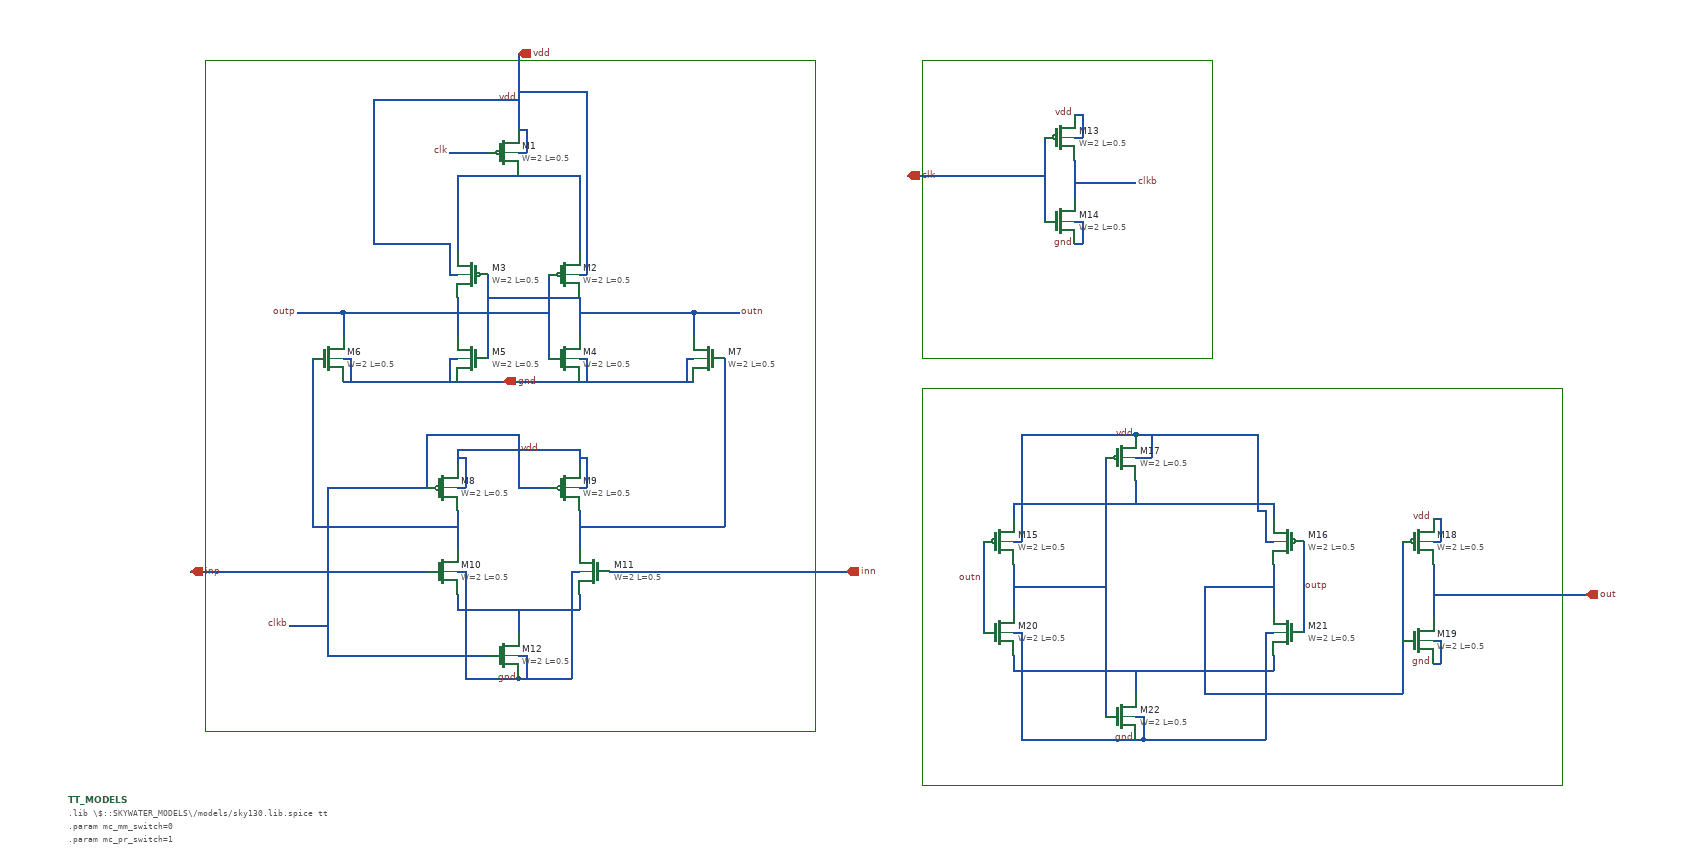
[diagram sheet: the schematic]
v {xschem version=3.4.1 file_version=1.2
}
G {}
K {}
V {}
S {}
E {}
L 4 1120 -1100 1120 -710 {}
L 4 1120 -710 1500 -710 {}
L 4 1500 -1100 1500 -710 {}
L 4 1120 -1100 1500 -1100 {}
L 4 180 -1100 180 -220 {}
L 4 180 -220 980 -220 {}
L 4 980 -1100 980 -220 {}
L 4 180 -1100 980 -1100 {}
L 4 1120 -670 1120 -150 {}
L 4 1120 -150 1960 -150 {}
L 4 1960 -670 1960 -150 {}
L 4 1120 -670 1960 -670 {}
N 510 -950 510 -850 {
lab=#net1}
N 510 -950 590 -950 {
lab=#net1}
N 590 -950 670 -950 {
lab=#net1}
N 670 -950 670 -850 {
lab=#net1}
N 510 -790 510 -740 {
lab=outp}
N 670 -790 670 -740 {
lab=outn}
N 550 -820 550 -710 {
lab=outn}
N 630 -820 630 -710 {
lab=outp}
N 510 -770 630 -770 {
lab=outp}
N 550 -790 670 -790 {
lab=outn}
N 360 -770 360 -740 {
lab=outp}
N 360 -770 510 -770 {
lab=outp}
N 670 -770 820 -770 {
lab=outn}
N 820 -770 820 -740 {
lab=outn}
N 360 -680 820 -680 {
lab=gnd}
N 510 -590 510 -570 {
lab=vdd}
N 510 -590 670 -590 {
lab=vdd}
N 670 -590 670 -570 {
lab=vdd}
N 470 -610 470 -540 {
lab=clkb}
N 470 -610 590 -610 {
lab=clkb}
N 590 -610 590 -540 {
lab=clkb}
N 590 -540 630 -540 {
lab=clkb}
N 510 -510 510 -460 {
lab=#net2}
N 670 -510 670 -460 {
lab=#net3}
N 320 -490 510 -490 {
lab=#net2}
N 320 -710 320 -490 {
lab=#net2}
N 670 -490 860 -490 {
lab=#net3}
N 860 -710 860 -490 {
lab=#net3}
N 510 -400 510 -380 {
lab=#net4}
N 510 -380 670 -380 {
lab=#net4}
N 670 -400 670 -380 {
lab=#net4}
N 590 -380 590 -350 {
lab=#net4}
N 340 -320 550 -320 {
lab=clkb}
N 340 -540 340 -320 {
lab=clkb}
N 340 -540 470 -540 {
lab=clkb}
N 820 -770 880 -770 {
lab=outn}
N 300 -770 360 -770 {
lab=outp}
N 710 -430 880 -430 {
lab=inn}
N 300 -430 470 -430 {
lab=inp}
N 1280 -1000 1280 -890 {
lab=clk}
N 1320 -970 1320 -920 {
lab=clkb}
N 1180 -950 1280 -950 {
lab=clk}
N 1320 -940 1400 -940 {
lab=clkb}
N 290 -360 340 -360 {
lab=clkb}
N 500 -980 550 -980 {
lab=clk}
N 1240 -520 1240 -500 {
lab=#net5}
N 1240 -520 1580 -520 {
lab=#net5}
N 1580 -520 1580 -500 {
lab=#net5}
N 1400 -550 1400 -520 {
lab=#net5}
N 1240 -440 1240 -380 {
lab=#net6}
N 1580 -440 1580 -380 {
lab=#net7}
N 1360 -580 1360 -240 {
lab=#net6}
N 1240 -320 1240 -300 {
lab=#net8}
N 1240 -300 1580 -300 {
lab=#net8}
N 1580 -320 1580 -300 {
lab=#net8}
N 1400 -300 1400 -270 {
lab=#net8}
N 1240 -410 1360 -410 {
lab=#net6}
N 1200 -470 1200 -350 {
lab=outn}
N 1620 -470 1620 -350 {
lab=outp}
N 1750 -470 1750 -340 {
lab=#net7}
N 1790 -440 1790 -370 {
lab=out}
N 1490 -410 1580 -410 {
lab=#net7}
N 1490 -410 1490 -270 {
lab=#net7}
N 1490 -270 1750 -270 {
lab=#net7}
N 1750 -340 1750 -270 {
lab=#net7}
N 1790 -400 1880 -400 {
lab=out}
N 1400 -580 1420 -580 {
lab=vdd}
N 1420 -610 1420 -580 {
lab=vdd}
N 1400 -610 1420 -610 {
lab=vdd}
N 1240 -470 1250 -470 {
lab=vdd}
N 1250 -510 1250 -470 {
lab=vdd}
N 1240 -350 1250 -350 {
lab=#net8}
N 1250 -350 1250 -310 {
lab=#net8}
N 1400 -240 1410 -240 {
lab=gnd}
N 1410 -240 1410 -210 {
lab=gnd}
N 1400 -210 1410 -210 {
lab=gnd}
N 1570 -350 1580 -350 {
lab=#net8}
N 1570 -350 1570 -310 {
lab=#net8}
N 1570 -470 1580 -470 {
lab=vdd}
N 1570 -510 1570 -470 {
lab=vdd}
N 1790 -470 1800 -470 {
lab=vdd}
N 1800 -500 1800 -470 {
lab=vdd}
N 1790 -500 1800 -500 {
lab=vdd}
N 1790 -340 1800 -340 {
lab=gnd}
N 1800 -340 1800 -310 {
lab=gnd}
N 1790 -310 1800 -310 {
lab=gnd}
N 590 -980 600 -980 {
lab=vdd}
N 600 -1010 600 -980 {
lab=vdd}
N 590 -1010 600 -1010 {
lab=vdd}
N 500 -820 510 -820 {
lab=vdd}
N 500 -860 500 -820 {
lab=vdd}
N 670 -820 680 -820 {
lab=vdd}
N 680 -860 680 -820 {
lab=vdd}
N 500 -710 510 -710 {
lab=gnd}
N 500 -710 500 -680 {
lab=gnd}
N 670 -710 680 -710 {
lab=gnd}
N 680 -710 680 -680 {
lab=gnd}
N 810 -710 820 -710 {
lab=gnd}
N 810 -710 810 -680 {
lab=gnd}
N 360 -710 370 -710 {
lab=gnd}
N 370 -710 370 -680 {
lab=gnd}
N 510 -540 520 -540 {
lab=vdd}
N 520 -580 520 -540 {
lab=vdd}
N 510 -580 520 -580 {
lab=vdd}
N 670 -540 680 -540 {
lab=vdd}
N 680 -580 680 -540 {
lab=vdd}
N 670 -580 680 -580 {
lab=vdd}
N 660 -430 670 -430 {
lab=#net4}
N 660 -430 660 -390 {
lab=#net4}
N 510 -430 520 -430 {
lab=#net4}
N 520 -430 520 -390 {
lab=#net4}
N 590 -320 600 -320 {
lab=gnd}
N 600 -320 600 -290 {
lab=gnd}
N 590 -290 600 -290 {
lab=gnd}
N 1320 -1000 1330 -1000 {
lab=vdd}
N 1330 -1030 1330 -1000 {
lab=vdd}
N 1320 -1030 1330 -1030 {
lab=vdd}
N 1320 -890 1330 -890 {
lab=gnd}
N 1330 -890 1330 -860 {
lab=gnd}
N 1320 -860 1330 -860 {
lab=gnd}
N 160 -430 300 -430 {
lab=inp}
N 880 -430 1020 -430 {
lab=inn}
N 1100 -950 1180 -950 {
lab=clk}
N 590 -1110 590 -1010 {
lab=vdd}
N 1880 -400 1990 -400 {
lab=out}
N 680 -1060 680 -860 {
lab=vdd}
N 590 -1060 680 -1060 {
lab=vdd}
N 400 -860 500 -860 {
lab=vdd}
N 400 -1050 400 -860 {
lab=vdd}
N 400 -1050 590 -1050 {
lab=vdd}
N 1250 -610 1250 -510 {
lab=vdd}
N 1250 -610 1400 -610 {
lab=vdd}
N 1400 -610 1560 -610 {
lab=vdd}
N 1560 -610 1560 -510 {
lab=vdd}
N 1560 -510 1570 -510 {
lab=vdd}
N 1250 -310 1250 -210 {}
N 1250 -210 1400 -210 {}
N 1570 -310 1570 -210 {}
N 1410 -210 1570 -210 {}
N 660 -390 660 -290 {}
N 590 -290 660 -290 {}
N 520 -390 520 -290 {}
N 520 -290 590 -290 {}
C {devices/code.sym} 0 -130 0 0 {name=TT_MODELS
only_toplevel=true
format="tcleval( @value )"
value=".lib \\\\$::SKYWATER_MODELS\\\\/models/sky130.lib.spice tt
.param mc_mm_switch=0
.param mc_pr_switch=1
"}
C {xschem_sky130/sky130_fd_pr/pfet_01v8.sym} 570 -980 0 0 {name=M1
L=0.5
W=2
nf=1
mult=1
ad="'int((nf+1)/2) * W/nf * 0.29'" 
pd="'2*int((nf+1)/2) * (W/nf + 0.29)'"
as="'int((nf+2)/2) * W/nf * 0.29'" 
ps="'2*int((nf+2)/2) * (W/nf + 0.29)'"
nrd="'0.29 / W'" nrs="'0.29 / W'"
sa=0 sb=0 sd=0
model=pfet_01v8
spiceprefix=X
}
C {xschem_sky130/sky130_fd_pr/pfet_01v8.sym} 650 -820 0 0 {name=M2
L=0.5
W=2
nf=1
mult=1
ad="'int((nf+1)/2) * W/nf * 0.29'" 
pd="'2*int((nf+1)/2) * (W/nf + 0.29)'"
as="'int((nf+2)/2) * W/nf * 0.29'" 
ps="'2*int((nf+2)/2) * (W/nf + 0.29)'"
nrd="'0.29 / W'" nrs="'0.29 / W'"
sa=0 sb=0 sd=0
model=pfet_01v8
spiceprefix=X
}
C {xschem_sky130/sky130_fd_pr/pfet_01v8.sym} 530 -820 0 1 {name=M3
L=0.5
W=2
nf=1
mult=1
ad="'int((nf+1)/2) * W/nf * 0.29'" 
pd="'2*int((nf+1)/2) * (W/nf + 0.29)'"
as="'int((nf+2)/2) * W/nf * 0.29'" 
ps="'2*int((nf+2)/2) * (W/nf + 0.29)'"
nrd="'0.29 / W'" nrs="'0.29 / W'"
sa=0 sb=0 sd=0
model=pfet_01v8
spiceprefix=X
}
C {xschem_sky130/sky130_fd_pr/nfet_01v8.sym} 650 -710 0 0 {name=M4
L=0.5
W=2
nf=1 
mult=1
ad="'int((nf+1)/2) * W/nf * 0.29'" 
pd="'2*int((nf+1)/2) * (W/nf + 0.29)'"
as="'int((nf+2)/2) * W/nf * 0.29'" 
ps="'2*int((nf+2)/2) * (W/nf + 0.29)'"
nrd="'0.29 / W'" nrs="'0.29 / W'"
sa=0 sb=0 sd=0
model=nfet_01v8
spiceprefix=X
}
C {xschem_sky130/sky130_fd_pr/nfet_01v8.sym} 530 -710 0 1 {name=M5
L=0.5
W=2
nf=1 
mult=1
ad="'int((nf+1)/2) * W/nf * 0.29'" 
pd="'2*int((nf+1)/2) * (W/nf + 0.29)'"
as="'int((nf+2)/2) * W/nf * 0.29'" 
ps="'2*int((nf+2)/2) * (W/nf + 0.29)'"
nrd="'0.29 / W'" nrs="'0.29 / W'"
sa=0 sb=0 sd=0
model=nfet_01v8
spiceprefix=X
}
C {xschem_sky130/sky130_fd_pr/nfet_01v8.sym} 340 -710 0 0 {name=M6
L=0.5
W=2
nf=1 
mult=1
ad="'int((nf+1)/2) * W/nf * 0.29'" 
pd="'2*int((nf+1)/2) * (W/nf + 0.29)'"
as="'int((nf+2)/2) * W/nf * 0.29'" 
ps="'2*int((nf+2)/2) * (W/nf + 0.29)'"
nrd="'0.29 / W'" nrs="'0.29 / W'"
sa=0 sb=0 sd=0
model=nfet_01v8
spiceprefix=X
}
C {xschem_sky130/sky130_fd_pr/nfet_01v8.sym} 840 -710 0 1 {name=M7
L=0.5
W=2
nf=1 
mult=1
ad="'int((nf+1)/2) * W/nf * 0.29'" 
pd="'2*int((nf+1)/2) * (W/nf + 0.29)'"
as="'int((nf+2)/2) * W/nf * 0.29'" 
ps="'2*int((nf+2)/2) * (W/nf + 0.29)'"
nrd="'0.29 / W'" nrs="'0.29 / W'"
sa=0 sb=0 sd=0
model=nfet_01v8
spiceprefix=X
}
C {xschem_sky130/sky130_fd_pr/pfet_01v8.sym} 490 -540 0 0 {name=M8
L=0.5
W=2
nf=1
mult=1
ad="'int((nf+1)/2) * W/nf * 0.29'" 
pd="'2*int((nf+1)/2) * (W/nf + 0.29)'"
as="'int((nf+2)/2) * W/nf * 0.29'" 
ps="'2*int((nf+2)/2) * (W/nf + 0.29)'"
nrd="'0.29 / W'" nrs="'0.29 / W'"
sa=0 sb=0 sd=0
model=pfet_01v8
spiceprefix=X
}
C {xschem_sky130/sky130_fd_pr/pfet_01v8.sym} 650 -540 0 0 {name=M9
L=0.5
W=2
nf=1
mult=1
ad="'int((nf+1)/2) * W/nf * 0.29'" 
pd="'2*int((nf+1)/2) * (W/nf + 0.29)'"
as="'int((nf+2)/2) * W/nf * 0.29'" 
ps="'2*int((nf+2)/2) * (W/nf + 0.29)'"
nrd="'0.29 / W'" nrs="'0.29 / W'"
sa=0 sb=0 sd=0
model=pfet_01v8
spiceprefix=X
}
C {xschem_sky130/sky130_fd_pr/nfet_01v8.sym} 490 -430 0 0 {name=M10
L=0.5
W=2
nf=1 
mult=1
ad="'int((nf+1)/2) * W/nf * 0.29'" 
pd="'2*int((nf+1)/2) * (W/nf + 0.29)'"
as="'int((nf+2)/2) * W/nf * 0.29'" 
ps="'2*int((nf+2)/2) * (W/nf + 0.29)'"
nrd="'0.29 / W'" nrs="'0.29 / W'"
sa=0 sb=0 sd=0
model=nfet_01v8
spiceprefix=X
}
C {xschem_sky130/sky130_fd_pr/nfet_01v8.sym} 690 -430 0 1 {name=M11
L=0.5
W=2
nf=1 
mult=1
ad="'int((nf+1)/2) * W/nf * 0.29'" 
pd="'2*int((nf+1)/2) * (W/nf + 0.29)'"
as="'int((nf+2)/2) * W/nf * 0.29'" 
ps="'2*int((nf+2)/2) * (W/nf + 0.29)'"
nrd="'0.29 / W'" nrs="'0.29 / W'"
sa=0 sb=0 sd=0
model=nfet_01v8
spiceprefix=X
}
C {xschem_sky130/sky130_fd_pr/nfet_01v8.sym} 570 -320 0 0 {name=M12
L=0.5
W=2
nf=1 
mult=1
ad="'int((nf+1)/2) * W/nf * 0.29'" 
pd="'2*int((nf+1)/2) * (W/nf + 0.29)'"
as="'int((nf+2)/2) * W/nf * 0.29'" 
ps="'2*int((nf+2)/2) * (W/nf + 0.29)'"
nrd="'0.29 / W'" nrs="'0.29 / W'"
sa=0 sb=0 sd=0
model=nfet_01v8
spiceprefix=X
}
C {devices/lab_pin.sym} 620 -590 1 0 {name=p2 sig_type=std_logic lab=vdd}
C {devices/lab_pin.sym} 300 -770 0 0 {name=p3 sig_type=std_logic lab=outp}
C {devices/lab_pin.sym} 880 -770 2 0 {name=p4 sig_type=std_logic lab=outn}
C {xschem_sky130/sky130_fd_pr/pfet_01v8.sym} 1300 -1000 0 0 {name=M13
L=0.5
W=2
nf=1
mult=1
ad="'int((nf+1)/2) * W/nf * 0.29'" 
pd="'2*int((nf+1)/2) * (W/nf + 0.29)'"
as="'int((nf+2)/2) * W/nf * 0.29'" 
ps="'2*int((nf+2)/2) * (W/nf + 0.29)'"
nrd="'0.29 / W'" nrs="'0.29 / W'"
sa=0 sb=0 sd=0
model=pfet_01v8
spiceprefix=X
}
C {xschem_sky130/sky130_fd_pr/nfet_01v8.sym} 1300 -890 0 0 {name=M14
L=0.5
W=2
nf=1 
mult=1
ad="'int((nf+1)/2) * W/nf * 0.29'" 
pd="'2*int((nf+1)/2) * (W/nf + 0.29)'"
as="'int((nf+2)/2) * W/nf * 0.29'" 
ps="'2*int((nf+2)/2) * (W/nf + 0.29)'"
nrd="'0.29 / W'" nrs="'0.29 / W'"
sa=0 sb=0 sd=0
model=nfet_01v8
spiceprefix=X
}
C {devices/lab_pin.sym} 1320 -1030 1 0 {name=p7 sig_type=std_logic lab=vdd}
C {devices/lab_pin.sym} 1400 -940 2 0 {name=p9 sig_type=std_logic lab=clkb}
C {devices/lab_pin.sym} 500 -980 0 0 {name=p11 sig_type=std_logic lab=clk}
C {devices/lab_pin.sym} 290 -360 0 0 {name=p12 sig_type=std_logic lab=clkb}
C {xschem_sky130/sky130_fd_pr/pfet_01v8.sym} 1220 -470 0 0 {name=M15
L=0.5
W=2
nf=1
mult=1
ad="'int((nf+1)/2) * W/nf * 0.29'" 
pd="'2*int((nf+1)/2) * (W/nf + 0.29)'"
as="'int((nf+2)/2) * W/nf * 0.29'" 
ps="'2*int((nf+2)/2) * (W/nf + 0.29)'"
nrd="'0.29 / W'" nrs="'0.29 / W'"
sa=0 sb=0 sd=0
model=pfet_01v8
spiceprefix=X
}
C {xschem_sky130/sky130_fd_pr/pfet_01v8.sym} 1600 -470 0 1 {name=M16
L=0.5
W=2
nf=1
mult=1
ad="'int((nf+1)/2) * W/nf * 0.29'" 
pd="'2*int((nf+1)/2) * (W/nf + 0.29)'"
as="'int((nf+2)/2) * W/nf * 0.29'" 
ps="'2*int((nf+2)/2) * (W/nf + 0.29)'"
nrd="'0.29 / W'" nrs="'0.29 / W'"
sa=0 sb=0 sd=0
model=pfet_01v8
spiceprefix=X
}
C {xschem_sky130/sky130_fd_pr/pfet_01v8.sym} 1380 -580 0 0 {name=M17
L=0.5
W=2
nf=1
mult=1
ad="'int((nf+1)/2) * W/nf * 0.29'" 
pd="'2*int((nf+1)/2) * (W/nf + 0.29)'"
as="'int((nf+2)/2) * W/nf * 0.29'" 
ps="'2*int((nf+2)/2) * (W/nf + 0.29)'"
nrd="'0.29 / W'" nrs="'0.29 / W'"
sa=0 sb=0 sd=0
model=pfet_01v8
spiceprefix=X
}
C {xschem_sky130/sky130_fd_pr/pfet_01v8.sym} 1770 -470 0 0 {name=M18
L=0.5
W=2
nf=1
mult=1
ad="'int((nf+1)/2) * W/nf * 0.29'" 
pd="'2*int((nf+1)/2) * (W/nf + 0.29)'"
as="'int((nf+2)/2) * W/nf * 0.29'" 
ps="'2*int((nf+2)/2) * (W/nf + 0.29)'"
nrd="'0.29 / W'" nrs="'0.29 / W'"
sa=0 sb=0 sd=0
model=pfet_01v8
spiceprefix=X
}
C {xschem_sky130/sky130_fd_pr/nfet_01v8.sym} 1770 -340 0 0 {name=M19
L=0.5
W=2
nf=1 
mult=1
ad="'int((nf+1)/2) * W/nf * 0.29'" 
pd="'2*int((nf+1)/2) * (W/nf + 0.29)'"
as="'int((nf+2)/2) * W/nf * 0.29'" 
ps="'2*int((nf+2)/2) * (W/nf + 0.29)'"
nrd="'0.29 / W'" nrs="'0.29 / W'"
sa=0 sb=0 sd=0
model=nfet_01v8
spiceprefix=X
}
C {xschem_sky130/sky130_fd_pr/nfet_01v8.sym} 1220 -350 0 0 {name=M20
L=0.5
W=2
nf=1 
mult=1
ad="'int((nf+1)/2) * W/nf * 0.29'" 
pd="'2*int((nf+1)/2) * (W/nf + 0.29)'"
as="'int((nf+2)/2) * W/nf * 0.29'" 
ps="'2*int((nf+2)/2) * (W/nf + 0.29)'"
nrd="'0.29 / W'" nrs="'0.29 / W'"
sa=0 sb=0 sd=0
model=nfet_01v8
spiceprefix=X
}
C {xschem_sky130/sky130_fd_pr/nfet_01v8.sym} 1600 -350 0 1 {name=M21
L=0.5
W=2
nf=1 
mult=1
ad="'int((nf+1)/2) * W/nf * 0.29'" 
pd="'2*int((nf+1)/2) * (W/nf + 0.29)'"
as="'int((nf+2)/2) * W/nf * 0.29'" 
ps="'2*int((nf+2)/2) * (W/nf + 0.29)'"
nrd="'0.29 / W'" nrs="'0.29 / W'"
sa=0 sb=0 sd=0
model=nfet_01v8
spiceprefix=X
}
C {xschem_sky130/sky130_fd_pr/nfet_01v8.sym} 1380 -240 0 0 {name=M22
L=0.5
W=2
nf=1 
mult=1
ad="'int((nf+1)/2) * W/nf * 0.29'" 
pd="'2*int((nf+1)/2) * (W/nf + 0.29)'"
as="'int((nf+2)/2) * W/nf * 0.29'" 
ps="'2*int((nf+2)/2) * (W/nf + 0.29)'"
nrd="'0.29 / W'" nrs="'0.29 / W'"
sa=0 sb=0 sd=0
model=nfet_01v8
spiceprefix=X
}
C {devices/lab_pin.sym} 1200 -420 0 0 {name=p13 sig_type=std_logic lab=outn}
C {devices/lab_pin.sym} 1620 -410 2 0 {name=p14 sig_type=std_logic lab=outp}
C {devices/lab_pin.sym} 1400 -610 1 0 {name=p15 sig_type=std_logic lab=vdd}
C {devices/lab_pin.sym} 1790 -500 1 0 {name=p17 sig_type=std_logic lab=vdd}
C {devices/opin.sym} 160 -430 2 0 {name=p19 lab=inp}
C {devices/opin.sym} 1020 -430 0 0 {name=p5 lab=inn}
C {devices/opin.sym} 1100 -950 2 0 {name=p18 lab=clk}
C {devices/opin.sym} 590 -1110 3 0 {name=p8 lab=vdd}
C {devices/lab_pin.sym} 590 -1050 0 0 {name=p1 sig_type=std_logic lab=vdd}
C {devices/opin.sym} 1990 -400 0 0 {name=p20 lab=out}
C {devices/lab_pin.sym} 590 -290 3 0 {name=p6 lab=gnd}
C {devices/lab_pin.sym} 1400 -210 3 0 {name=p10 lab=gnd}
C {devices/lab_pin.sym} 1790 -310 3 0 {name=p16 lab=gnd}
C {devices/lab_pin.sym} 1320 -860 3 0 {name=p21 lab=gnd}
C {devices/opin.sym} 570 -680 1 0 {name=p22 lab=gnd}
